VERSION 5.7 ;
BUSBITCHARS "[]" ;
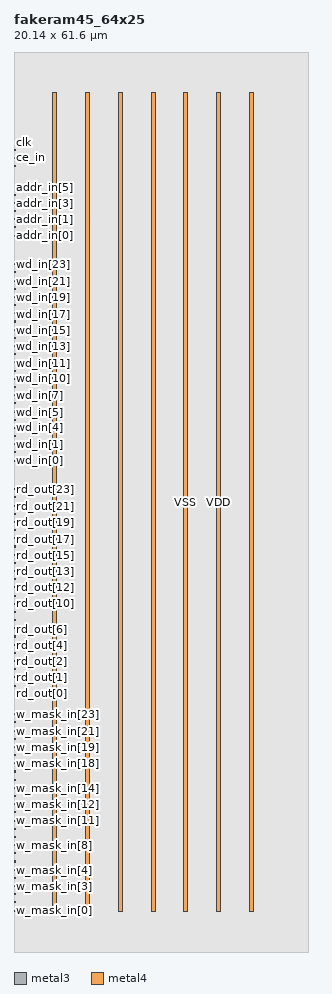
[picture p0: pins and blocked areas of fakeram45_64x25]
MACRO fakeram45_64x25
  FOREIGN fakeram45_64x25 0 0 ;
  SYMMETRY X Y R90 ;
  SIZE 20.140 BY 61.600 ;
  CLASS BLOCK ;
  PIN w_mask_in[0]
    DIRECTION INPUT ;
    USE SIGNAL ;
    SHAPE ABUTMENT ;
    PORT
      LAYER metal3 ;
      RECT 0.000 2.800 0.070 2.870 ;
    END
  END w_mask_in[0]
  PIN w_mask_in[1]
    DIRECTION INPUT ;
    USE SIGNAL ;
    SHAPE ABUTMENT ;
    PORT
      LAYER metal3 ;
      RECT 0.000 3.360 0.070 3.430 ;
    END
  END w_mask_in[1]
  PIN w_mask_in[2]
    DIRECTION INPUT ;
    USE SIGNAL ;
    SHAPE ABUTMENT ;
    PORT
      LAYER metal3 ;
      RECT 0.000 3.920 0.070 3.990 ;
    END
  END w_mask_in[2]
  PIN w_mask_in[3]
    DIRECTION INPUT ;
    USE SIGNAL ;
    SHAPE ABUTMENT ;
    PORT
      LAYER metal3 ;
      RECT 0.000 4.480 0.070 4.550 ;
    END
  END w_mask_in[3]
  PIN w_mask_in[4]
    DIRECTION INPUT ;
    USE SIGNAL ;
    SHAPE ABUTMENT ;
    PORT
      LAYER metal3 ;
      RECT 0.000 5.040 0.070 5.110 ;
    END
  END w_mask_in[4]
  PIN w_mask_in[5]
    DIRECTION INPUT ;
    USE SIGNAL ;
    SHAPE ABUTMENT ;
    PORT
      LAYER metal3 ;
      RECT 0.000 5.600 0.070 5.670 ;
    END
  END w_mask_in[5]
  PIN w_mask_in[6]
    DIRECTION INPUT ;
    USE SIGNAL ;
    SHAPE ABUTMENT ;
    PORT
      LAYER metal3 ;
      RECT 0.000 6.160 0.070 6.230 ;
    END
  END w_mask_in[6]
  PIN w_mask_in[7]
    DIRECTION INPUT ;
    USE SIGNAL ;
    SHAPE ABUTMENT ;
    PORT
      LAYER metal3 ;
      RECT 0.000 6.720 0.070 6.790 ;
    END
  END w_mask_in[7]
  PIN w_mask_in[8]
    DIRECTION INPUT ;
    USE SIGNAL ;
    SHAPE ABUTMENT ;
    PORT
      LAYER metal3 ;
      RECT 0.000 7.280 0.070 7.350 ;
    END
  END w_mask_in[8]
  PIN w_mask_in[9]
    DIRECTION INPUT ;
    USE SIGNAL ;
    SHAPE ABUTMENT ;
    PORT
      LAYER metal3 ;
      RECT 0.000 7.840 0.070 7.910 ;
    END
  END w_mask_in[9]
  PIN w_mask_in[10]
    DIRECTION INPUT ;
    USE SIGNAL ;
    SHAPE ABUTMENT ;
    PORT
      LAYER metal3 ;
      RECT 0.000 8.400 0.070 8.470 ;
    END
  END w_mask_in[10]
  PIN w_mask_in[11]
    DIRECTION INPUT ;
    USE SIGNAL ;
    SHAPE ABUTMENT ;
    PORT
      LAYER metal3 ;
      RECT 0.000 8.960 0.070 9.030 ;
    END
  END w_mask_in[11]
  PIN w_mask_in[12]
    DIRECTION INPUT ;
    USE SIGNAL ;
    SHAPE ABUTMENT ;
    PORT
      LAYER metal3 ;
      RECT 0.000 9.520 0.070 9.590 ;
    END
  END w_mask_in[12]
  PIN w_mask_in[13]
    DIRECTION INPUT ;
    USE SIGNAL ;
    SHAPE ABUTMENT ;
    PORT
      LAYER metal3 ;
      RECT 0.000 10.080 0.070 10.150 ;
    END
  END w_mask_in[13]
  PIN w_mask_in[14]
    DIRECTION INPUT ;
    USE SIGNAL ;
    SHAPE ABUTMENT ;
    PORT
      LAYER metal3 ;
      RECT 0.000 10.640 0.070 10.710 ;
    END
  END w_mask_in[14]
  PIN w_mask_in[15]
    DIRECTION INPUT ;
    USE SIGNAL ;
    SHAPE ABUTMENT ;
    PORT
      LAYER metal3 ;
      RECT 0.000 11.200 0.070 11.270 ;
    END
  END w_mask_in[15]
  PIN w_mask_in[16]
    DIRECTION INPUT ;
    USE SIGNAL ;
    SHAPE ABUTMENT ;
    PORT
      LAYER metal3 ;
      RECT 0.000 11.760 0.070 11.830 ;
    END
  END w_mask_in[16]
  PIN w_mask_in[17]
    DIRECTION INPUT ;
    USE SIGNAL ;
    SHAPE ABUTMENT ;
    PORT
      LAYER metal3 ;
      RECT 0.000 12.320 0.070 12.390 ;
    END
  END w_mask_in[17]
  PIN w_mask_in[18]
    DIRECTION INPUT ;
    USE SIGNAL ;
    SHAPE ABUTMENT ;
    PORT
      LAYER metal3 ;
      RECT 0.000 12.880 0.070 12.950 ;
    END
  END w_mask_in[18]
  PIN w_mask_in[19]
    DIRECTION INPUT ;
    USE SIGNAL ;
    SHAPE ABUTMENT ;
    PORT
      LAYER metal3 ;
      RECT 0.000 13.440 0.070 13.510 ;
    END
  END w_mask_in[19]
  PIN w_mask_in[20]
    DIRECTION INPUT ;
    USE SIGNAL ;
    SHAPE ABUTMENT ;
    PORT
      LAYER metal3 ;
      RECT 0.000 14.000 0.070 14.070 ;
    END
  END w_mask_in[20]
  PIN w_mask_in[21]
    DIRECTION INPUT ;
    USE SIGNAL ;
    SHAPE ABUTMENT ;
    PORT
      LAYER metal3 ;
      RECT 0.000 14.560 0.070 14.630 ;
    END
  END w_mask_in[21]
  PIN w_mask_in[22]
    DIRECTION INPUT ;
    USE SIGNAL ;
    SHAPE ABUTMENT ;
    PORT
      LAYER metal3 ;
      RECT 0.000 15.120 0.070 15.190 ;
    END
  END w_mask_in[22]
  PIN w_mask_in[23]
    DIRECTION INPUT ;
    USE SIGNAL ;
    SHAPE ABUTMENT ;
    PORT
      LAYER metal3 ;
      RECT 0.000 15.680 0.070 15.750 ;
    END
  END w_mask_in[23]
  PIN w_mask_in[24]
    DIRECTION INPUT ;
    USE SIGNAL ;
    SHAPE ABUTMENT ;
    PORT
      LAYER metal3 ;
      RECT 0.000 16.240 0.070 16.310 ;
    END
  END w_mask_in[24]
  PIN rd_out[0]
    DIRECTION OUTPUT ;
    USE SIGNAL ;
    SHAPE ABUTMENT ;
    PORT
      LAYER metal3 ;
      RECT 0.000 18.200 0.070 18.270 ;
    END
  END rd_out[0]
  PIN rd_out[1]
    DIRECTION OUTPUT ;
    USE SIGNAL ;
    SHAPE ABUTMENT ;
    PORT
      LAYER metal3 ;
      RECT 0.000 18.760 0.070 18.830 ;
    END
  END rd_out[1]
  PIN rd_out[2]
    DIRECTION OUTPUT ;
    USE SIGNAL ;
    SHAPE ABUTMENT ;
    PORT
      LAYER metal3 ;
      RECT 0.000 19.320 0.070 19.390 ;
    END
  END rd_out[2]
  PIN rd_out[3]
    DIRECTION OUTPUT ;
    USE SIGNAL ;
    SHAPE ABUTMENT ;
    PORT
      LAYER metal3 ;
      RECT 0.000 19.880 0.070 19.950 ;
    END
  END rd_out[3]
  PIN rd_out[4]
    DIRECTION OUTPUT ;
    USE SIGNAL ;
    SHAPE ABUTMENT ;
    PORT
      LAYER metal3 ;
      RECT 0.000 20.440 0.070 20.510 ;
    END
  END rd_out[4]
  PIN rd_out[5]
    DIRECTION OUTPUT ;
    USE SIGNAL ;
    SHAPE ABUTMENT ;
    PORT
      LAYER metal3 ;
      RECT 0.000 21.000 0.070 21.070 ;
    END
  END rd_out[5]
  PIN rd_out[6]
    DIRECTION OUTPUT ;
    USE SIGNAL ;
    SHAPE ABUTMENT ;
    PORT
      LAYER metal3 ;
      RECT 0.000 21.560 0.070 21.630 ;
    END
  END rd_out[6]
  PIN rd_out[7]
    DIRECTION OUTPUT ;
    USE SIGNAL ;
    SHAPE ABUTMENT ;
    PORT
      LAYER metal3 ;
      RECT 0.000 22.120 0.070 22.190 ;
    END
  END rd_out[7]
  PIN rd_out[8]
    DIRECTION OUTPUT ;
    USE SIGNAL ;
    SHAPE ABUTMENT ;
    PORT
      LAYER metal3 ;
      RECT 0.000 22.680 0.070 22.750 ;
    END
  END rd_out[8]
  PIN rd_out[9]
    DIRECTION OUTPUT ;
    USE SIGNAL ;
    SHAPE ABUTMENT ;
    PORT
      LAYER metal3 ;
      RECT 0.000 23.240 0.070 23.310 ;
    END
  END rd_out[9]
  PIN rd_out[10]
    DIRECTION OUTPUT ;
    USE SIGNAL ;
    SHAPE ABUTMENT ;
    PORT
      LAYER metal3 ;
      RECT 0.000 23.800 0.070 23.870 ;
    END
  END rd_out[10]
  PIN rd_out[11]
    DIRECTION OUTPUT ;
    USE SIGNAL ;
    SHAPE ABUTMENT ;
    PORT
      LAYER metal3 ;
      RECT 0.000 24.360 0.070 24.430 ;
    END
  END rd_out[11]
  PIN rd_out[12]
    DIRECTION OUTPUT ;
    USE SIGNAL ;
    SHAPE ABUTMENT ;
    PORT
      LAYER metal3 ;
      RECT 0.000 24.920 0.070 24.990 ;
    END
  END rd_out[12]
  PIN rd_out[13]
    DIRECTION OUTPUT ;
    USE SIGNAL ;
    SHAPE ABUTMENT ;
    PORT
      LAYER metal3 ;
      RECT 0.000 25.480 0.070 25.550 ;
    END
  END rd_out[13]
  PIN rd_out[14]
    DIRECTION OUTPUT ;
    USE SIGNAL ;
    SHAPE ABUTMENT ;
    PORT
      LAYER metal3 ;
      RECT 0.000 26.040 0.070 26.110 ;
    END
  END rd_out[14]
  PIN rd_out[15]
    DIRECTION OUTPUT ;
    USE SIGNAL ;
    SHAPE ABUTMENT ;
    PORT
      LAYER metal3 ;
      RECT 0.000 26.600 0.070 26.670 ;
    END
  END rd_out[15]
  PIN rd_out[16]
    DIRECTION OUTPUT ;
    USE SIGNAL ;
    SHAPE ABUTMENT ;
    PORT
      LAYER metal3 ;
      RECT 0.000 27.160 0.070 27.230 ;
    END
  END rd_out[16]
  PIN rd_out[17]
    DIRECTION OUTPUT ;
    USE SIGNAL ;
    SHAPE ABUTMENT ;
    PORT
      LAYER metal3 ;
      RECT 0.000 27.720 0.070 27.790 ;
    END
  END rd_out[17]
  PIN rd_out[18]
    DIRECTION OUTPUT ;
    USE SIGNAL ;
    SHAPE ABUTMENT ;
    PORT
      LAYER metal3 ;
      RECT 0.000 28.280 0.070 28.350 ;
    END
  END rd_out[18]
  PIN rd_out[19]
    DIRECTION OUTPUT ;
    USE SIGNAL ;
    SHAPE ABUTMENT ;
    PORT
      LAYER metal3 ;
      RECT 0.000 28.840 0.070 28.910 ;
    END
  END rd_out[19]
  PIN rd_out[20]
    DIRECTION OUTPUT ;
    USE SIGNAL ;
    SHAPE ABUTMENT ;
    PORT
      LAYER metal3 ;
      RECT 0.000 29.400 0.070 29.470 ;
    END
  END rd_out[20]
  PIN rd_out[21]
    DIRECTION OUTPUT ;
    USE SIGNAL ;
    SHAPE ABUTMENT ;
    PORT
      LAYER metal3 ;
      RECT 0.000 29.960 0.070 30.030 ;
    END
  END rd_out[21]
  PIN rd_out[22]
    DIRECTION OUTPUT ;
    USE SIGNAL ;
    SHAPE ABUTMENT ;
    PORT
      LAYER metal3 ;
      RECT 0.000 30.520 0.070 30.590 ;
    END
  END rd_out[22]
  PIN rd_out[23]
    DIRECTION OUTPUT ;
    USE SIGNAL ;
    SHAPE ABUTMENT ;
    PORT
      LAYER metal3 ;
      RECT 0.000 31.080 0.070 31.150 ;
    END
  END rd_out[23]
  PIN rd_out[24]
    DIRECTION OUTPUT ;
    USE SIGNAL ;
    SHAPE ABUTMENT ;
    PORT
      LAYER metal3 ;
      RECT 0.000 31.640 0.070 31.710 ;
    END
  END rd_out[24]
  PIN wd_in[0]
    DIRECTION INPUT ;
    USE SIGNAL ;
    SHAPE ABUTMENT ;
    PORT
      LAYER metal3 ;
      RECT 0.000 33.600 0.070 33.670 ;
    END
  END wd_in[0]
  PIN wd_in[1]
    DIRECTION INPUT ;
    USE SIGNAL ;
    SHAPE ABUTMENT ;
    PORT
      LAYER metal3 ;
      RECT 0.000 34.160 0.070 34.230 ;
    END
  END wd_in[1]
  PIN wd_in[2]
    DIRECTION INPUT ;
    USE SIGNAL ;
    SHAPE ABUTMENT ;
    PORT
      LAYER metal3 ;
      RECT 0.000 34.720 0.070 34.790 ;
    END
  END wd_in[2]
  PIN wd_in[3]
    DIRECTION INPUT ;
    USE SIGNAL ;
    SHAPE ABUTMENT ;
    PORT
      LAYER metal3 ;
      RECT 0.000 35.280 0.070 35.350 ;
    END
  END wd_in[3]
  PIN wd_in[4]
    DIRECTION INPUT ;
    USE SIGNAL ;
    SHAPE ABUTMENT ;
    PORT
      LAYER metal3 ;
      RECT 0.000 35.840 0.070 35.910 ;
    END
  END wd_in[4]
  PIN wd_in[5]
    DIRECTION INPUT ;
    USE SIGNAL ;
    SHAPE ABUTMENT ;
    PORT
      LAYER metal3 ;
      RECT 0.000 36.400 0.070 36.470 ;
    END
  END wd_in[5]
  PIN wd_in[6]
    DIRECTION INPUT ;
    USE SIGNAL ;
    SHAPE ABUTMENT ;
    PORT
      LAYER metal3 ;
      RECT 0.000 36.960 0.070 37.030 ;
    END
  END wd_in[6]
  PIN wd_in[7]
    DIRECTION INPUT ;
    USE SIGNAL ;
    SHAPE ABUTMENT ;
    PORT
      LAYER metal3 ;
      RECT 0.000 37.520 0.070 37.590 ;
    END
  END wd_in[7]
  PIN wd_in[8]
    DIRECTION INPUT ;
    USE SIGNAL ;
    SHAPE ABUTMENT ;
    PORT
      LAYER metal3 ;
      RECT 0.000 38.080 0.070 38.150 ;
    END
  END wd_in[8]
  PIN wd_in[9]
    DIRECTION INPUT ;
    USE SIGNAL ;
    SHAPE ABUTMENT ;
    PORT
      LAYER metal3 ;
      RECT 0.000 38.640 0.070 38.710 ;
    END
  END wd_in[9]
  PIN wd_in[10]
    DIRECTION INPUT ;
    USE SIGNAL ;
    SHAPE ABUTMENT ;
    PORT
      LAYER metal3 ;
      RECT 0.000 39.200 0.070 39.270 ;
    END
  END wd_in[10]
  PIN wd_in[11]
    DIRECTION INPUT ;
    USE SIGNAL ;
    SHAPE ABUTMENT ;
    PORT
      LAYER metal3 ;
      RECT 0.000 39.760 0.070 39.830 ;
    END
  END wd_in[11]
  PIN wd_in[12]
    DIRECTION INPUT ;
    USE SIGNAL ;
    SHAPE ABUTMENT ;
    PORT
      LAYER metal3 ;
      RECT 0.000 40.320 0.070 40.390 ;
    END
  END wd_in[12]
  PIN wd_in[13]
    DIRECTION INPUT ;
    USE SIGNAL ;
    SHAPE ABUTMENT ;
    PORT
      LAYER metal3 ;
      RECT 0.000 40.880 0.070 40.950 ;
    END
  END wd_in[13]
  PIN wd_in[14]
    DIRECTION INPUT ;
    USE SIGNAL ;
    SHAPE ABUTMENT ;
    PORT
      LAYER metal3 ;
      RECT 0.000 41.440 0.070 41.510 ;
    END
  END wd_in[14]
  PIN wd_in[15]
    DIRECTION INPUT ;
    USE SIGNAL ;
    SHAPE ABUTMENT ;
    PORT
      LAYER metal3 ;
      RECT 0.000 42.000 0.070 42.070 ;
    END
  END wd_in[15]
  PIN wd_in[16]
    DIRECTION INPUT ;
    USE SIGNAL ;
    SHAPE ABUTMENT ;
    PORT
      LAYER metal3 ;
      RECT 0.000 42.560 0.070 42.630 ;
    END
  END wd_in[16]
  PIN wd_in[17]
    DIRECTION INPUT ;
    USE SIGNAL ;
    SHAPE ABUTMENT ;
    PORT
      LAYER metal3 ;
      RECT 0.000 43.120 0.070 43.190 ;
    END
  END wd_in[17]
  PIN wd_in[18]
    DIRECTION INPUT ;
    USE SIGNAL ;
    SHAPE ABUTMENT ;
    PORT
      LAYER metal3 ;
      RECT 0.000 43.680 0.070 43.750 ;
    END
  END wd_in[18]
  PIN wd_in[19]
    DIRECTION INPUT ;
    USE SIGNAL ;
    SHAPE ABUTMENT ;
    PORT
      LAYER metal3 ;
      RECT 0.000 44.240 0.070 44.310 ;
    END
  END wd_in[19]
  PIN wd_in[20]
    DIRECTION INPUT ;
    USE SIGNAL ;
    SHAPE ABUTMENT ;
    PORT
      LAYER metal3 ;
      RECT 0.000 44.800 0.070 44.870 ;
    END
  END wd_in[20]
  PIN wd_in[21]
    DIRECTION INPUT ;
    USE SIGNAL ;
    SHAPE ABUTMENT ;
    PORT
      LAYER metal3 ;
      RECT 0.000 45.360 0.070 45.430 ;
    END
  END wd_in[21]
  PIN wd_in[22]
    DIRECTION INPUT ;
    USE SIGNAL ;
    SHAPE ABUTMENT ;
    PORT
      LAYER metal3 ;
      RECT 0.000 45.920 0.070 45.990 ;
    END
  END wd_in[22]
  PIN wd_in[23]
    DIRECTION INPUT ;
    USE SIGNAL ;
    SHAPE ABUTMENT ;
    PORT
      LAYER metal3 ;
      RECT 0.000 46.480 0.070 46.550 ;
    END
  END wd_in[23]
  PIN wd_in[24]
    DIRECTION INPUT ;
    USE SIGNAL ;
    SHAPE ABUTMENT ;
    PORT
      LAYER metal3 ;
      RECT 0.000 47.040 0.070 47.110 ;
    END
  END wd_in[24]
  PIN addr_in[0]
    DIRECTION INPUT ;
    USE SIGNAL ;
    SHAPE ABUTMENT ;
    PORT
      LAYER metal3 ;
      RECT 0.000 49.000 0.070 49.070 ;
    END
  END addr_in[0]
  PIN addr_in[1]
    DIRECTION INPUT ;
    USE SIGNAL ;
    SHAPE ABUTMENT ;
    PORT
      LAYER metal3 ;
      RECT 0.000 49.560 0.070 49.630 ;
    END
  END addr_in[1]
  PIN addr_in[2]
    DIRECTION INPUT ;
    USE SIGNAL ;
    SHAPE ABUTMENT ;
    PORT
      LAYER metal3 ;
      RECT 0.000 50.120 0.070 50.190 ;
    END
  END addr_in[2]
  PIN addr_in[3]
    DIRECTION INPUT ;
    USE SIGNAL ;
    SHAPE ABUTMENT ;
    PORT
      LAYER metal3 ;
      RECT 0.000 50.680 0.070 50.750 ;
    END
  END addr_in[3]
  PIN addr_in[4]
    DIRECTION INPUT ;
    USE SIGNAL ;
    SHAPE ABUTMENT ;
    PORT
      LAYER metal3 ;
      RECT 0.000 51.240 0.070 51.310 ;
    END
  END addr_in[4]
  PIN addr_in[5]
    DIRECTION INPUT ;
    USE SIGNAL ;
    SHAPE ABUTMENT ;
    PORT
      LAYER metal3 ;
      RECT 0.000 51.800 0.070 51.870 ;
    END
  END addr_in[5]
  PIN we_in
    DIRECTION INPUT ;
    USE SIGNAL ;
    SHAPE ABUTMENT ;
    PORT
      LAYER metal3 ;
      RECT 0.000 53.760 0.070 53.830 ;
    END
  END we_in
  PIN ce_in
    DIRECTION INPUT ;
    USE SIGNAL ;
    SHAPE ABUTMENT ;
    PORT
      LAYER metal3 ;
      RECT 0.000 54.320 0.070 54.390 ;
    END
  END ce_in
  PIN clk
    DIRECTION INPUT ;
    USE SIGNAL ;
    SHAPE ABUTMENT ;
    PORT
      LAYER metal3 ;
      RECT 0.000 54.880 0.070 54.950 ;
    END
  END clk
  PIN VSS
    DIRECTION INOUT ;
    USE GROUND ;
    PORT
      LAYER metal4 ;
      RECT 2.660 2.800 2.940 58.800 ;
      RECT 7.140 2.800 7.420 58.800 ;
      RECT 11.620 2.800 11.900 58.800 ;
      RECT 16.100 2.800 16.380 58.800 ;
    END
  END VSS
  PIN VDD
    DIRECTION INOUT ;
    USE POWER ;
    PORT
      LAYER metal4 ;
      RECT 4.900 2.800 5.180 58.800 ;
      RECT 9.380 2.800 9.660 58.800 ;
      RECT 13.860 2.800 14.140 58.800 ;
    END
  END VDD
  OBS
    LAYER metal1 ;
    RECT 0 0 20.140 61.600 ;
    LAYER metal2 ;
    RECT 0 0 20.140 61.600 ;
    LAYER metal3 ;
    RECT 0.070 0 20.140 61.600 ;
    RECT 0 0.000 0.070 2.800 ;
    RECT 0 2.870 0.070 3.360 ;
    RECT 0 3.430 0.070 3.920 ;
    RECT 0 3.990 0.070 4.480 ;
    RECT 0 4.550 0.070 5.040 ;
    RECT 0 5.110 0.070 5.600 ;
    RECT 0 5.670 0.070 6.160 ;
    RECT 0 6.230 0.070 6.720 ;
    RECT 0 6.790 0.070 7.280 ;
    RECT 0 7.350 0.070 7.840 ;
    RECT 0 7.910 0.070 8.400 ;
    RECT 0 8.470 0.070 8.960 ;
    RECT 0 9.030 0.070 9.520 ;
    RECT 0 9.590 0.070 10.080 ;
    RECT 0 10.150 0.070 10.640 ;
    RECT 0 10.710 0.070 11.200 ;
    RECT 0 11.270 0.070 11.760 ;
    RECT 0 11.830 0.070 12.320 ;
    RECT 0 12.390 0.070 12.880 ;
    RECT 0 12.950 0.070 13.440 ;
    RECT 0 13.510 0.070 14.000 ;
    RECT 0 14.070 0.070 14.560 ;
    RECT 0 14.630 0.070 15.120 ;
    RECT 0 15.190 0.070 15.680 ;
    RECT 0 15.750 0.070 16.240 ;
    RECT 0 16.310 0.070 18.200 ;
    RECT 0 18.270 0.070 18.760 ;
    RECT 0 18.830 0.070 19.320 ;
    RECT 0 19.390 0.070 19.880 ;
    RECT 0 19.950 0.070 20.440 ;
    RECT 0 20.510 0.070 21.000 ;
    RECT 0 21.070 0.070 21.560 ;
    RECT 0 21.630 0.070 22.120 ;
    RECT 0 22.190 0.070 22.680 ;
    RECT 0 22.750 0.070 23.240 ;
    RECT 0 23.310 0.070 23.800 ;
    RECT 0 23.870 0.070 24.360 ;
    RECT 0 24.430 0.070 24.920 ;
    RECT 0 24.990 0.070 25.480 ;
    RECT 0 25.550 0.070 26.040 ;
    RECT 0 26.110 0.070 26.600 ;
    RECT 0 26.670 0.070 27.160 ;
    RECT 0 27.230 0.070 27.720 ;
    RECT 0 27.790 0.070 28.280 ;
    RECT 0 28.350 0.070 28.840 ;
    RECT 0 28.910 0.070 29.400 ;
    RECT 0 29.470 0.070 29.960 ;
    RECT 0 30.030 0.070 30.520 ;
    RECT 0 30.590 0.070 31.080 ;
    RECT 0 31.150 0.070 31.640 ;
    RECT 0 31.710 0.070 33.600 ;
    RECT 0 33.670 0.070 34.160 ;
    RECT 0 34.230 0.070 34.720 ;
    RECT 0 34.790 0.070 35.280 ;
    RECT 0 35.350 0.070 35.840 ;
    RECT 0 35.910 0.070 36.400 ;
    RECT 0 36.470 0.070 36.960 ;
    RECT 0 37.030 0.070 37.520 ;
    RECT 0 37.590 0.070 38.080 ;
    RECT 0 38.150 0.070 38.640 ;
    RECT 0 38.710 0.070 39.200 ;
    RECT 0 39.270 0.070 39.760 ;
    RECT 0 39.830 0.070 40.320 ;
    RECT 0 40.390 0.070 40.880 ;
    RECT 0 40.950 0.070 41.440 ;
    RECT 0 41.510 0.070 42.000 ;
    RECT 0 42.070 0.070 42.560 ;
    RECT 0 42.630 0.070 43.120 ;
    RECT 0 43.190 0.070 43.680 ;
    RECT 0 43.750 0.070 44.240 ;
    RECT 0 44.310 0.070 44.800 ;
    RECT 0 44.870 0.070 45.360 ;
    RECT 0 45.430 0.070 45.920 ;
    RECT 0 45.990 0.070 46.480 ;
    RECT 0 46.550 0.070 47.040 ;
    RECT 0 47.110 0.070 49.000 ;
    RECT 0 49.070 0.070 49.560 ;
    RECT 0 49.630 0.070 50.120 ;
    RECT 0 50.190 0.070 50.680 ;
    RECT 0 50.750 0.070 51.240 ;
    RECT 0 51.310 0.070 51.800 ;
    RECT 0 51.870 0.070 53.760 ;
    RECT 0 53.830 0.070 54.320 ;
    RECT 0 54.390 0.070 54.880 ;
    RECT 0 54.950 0.070 61.600 ;
    LAYER metal4 ;
    RECT 0 0 20.140 2.800 ;
    RECT 0 58.800 20.140 61.600 ;
    RECT 0.000 2.800 2.660 58.800 ;
    RECT 2.940 2.800 4.900 58.800 ;
    RECT 5.180 2.800 7.140 58.800 ;
    RECT 7.420 2.800 9.380 58.800 ;
    RECT 9.660 2.800 11.620 58.800 ;
    RECT 11.900 2.800 13.860 58.800 ;
    RECT 14.140 2.800 16.100 58.800 ;
    RECT 16.380 2.800 20.140 58.800 ;
    LAYER OVERLAP ;
    RECT 0 0 20.140 61.600 ;
  END
END fakeram45_64x25

END LIBRARY
